VERSION 5.7 ;
BUSBITCHARS "[]" ;
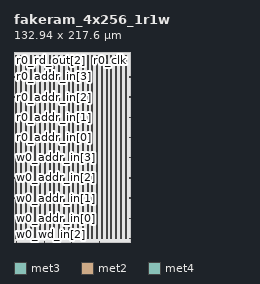
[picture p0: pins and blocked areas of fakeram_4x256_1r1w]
MACRO fakeram_4x256_1r1w
  FOREIGN fakeram_4x256_1r1w 0 0 ;
  SYMMETRY X Y R90 ;
  SIZE 132.940 BY 217.600 ;
  CLASS BLOCK ;
  PIN w0_wd_in[0]
    DIRECTION INPUT ;
    USE SIGNAL ;
    SHAPE ABUTMENT ;
    PORT
      LAYER met3 ;
      RECT 0.000 3.930 0.900 4.230 ;
    END
  END w0_wd_in[0]
  PIN w0_wd_in[1]
    DIRECTION INPUT ;
    USE SIGNAL ;
    SHAPE ABUTMENT ;
    PORT
      LAYER met3 ;
      RECT 132.040 3.930 132.940 4.230 ;
    END
  END w0_wd_in[1]
  PIN w0_wd_in[2]
    DIRECTION INPUT ;
    USE SIGNAL ;
    SHAPE ABUTMENT ;
    PORT
      LAYER met2 ;
      RECT 2.690 0.000 2.830 0.420 ;
    END
  END w0_wd_in[2]
  PIN w0_wd_in[3]
    DIRECTION INPUT ;
    USE SIGNAL ;
    SHAPE ABUTMENT ;
    PORT
      LAYER met2 ;
      RECT 34.430 0.000 34.570 0.420 ;
    END
  END w0_wd_in[3]
  PIN r0_rd_out[0]
    DIRECTION OUTPUT ;
    USE SIGNAL ;
    SHAPE ABUTMENT ;
    PORT
      LAYER met2 ;
      RECT 66.170 0.000 66.310 0.420 ;
    END
  END r0_rd_out[0]
  PIN r0_rd_out[1]
    DIRECTION OUTPUT ;
    USE SIGNAL ;
    SHAPE ABUTMENT ;
    PORT
      LAYER met2 ;
      RECT 97.910 0.000 98.050 0.420 ;
    END
  END r0_rd_out[1]
  PIN r0_rd_out[2]
    DIRECTION OUTPUT ;
    USE SIGNAL ;
    SHAPE ABUTMENT ;
    PORT
      LAYER met2 ;
      RECT 2.690 217.180 2.830 217.600 ;
    END
  END r0_rd_out[2]
  PIN r0_rd_out[3]
    DIRECTION OUTPUT ;
    USE SIGNAL ;
    SHAPE ABUTMENT ;
    PORT
      LAYER met2 ;
      RECT 20.630 217.180 20.770 217.600 ;
    END
  END r0_rd_out[3]
  PIN w0_addr_in[0]
    DIRECTION INPUT ;
    USE SIGNAL ;
    SHAPE ABUTMENT ;
    PORT
      LAYER met3 ;
      RECT 0.000 27.050 0.900 27.350 ;
    END
  END w0_addr_in[0]
  PIN w0_addr_in[1]
    DIRECTION INPUT ;
    USE SIGNAL ;
    SHAPE ABUTMENT ;
    PORT
      LAYER met3 ;
      RECT 0.000 50.170 0.900 50.470 ;
    END
  END w0_addr_in[1]
  PIN w0_addr_in[2]
    DIRECTION INPUT ;
    USE SIGNAL ;
    SHAPE ABUTMENT ;
    PORT
      LAYER met3 ;
      RECT 0.000 73.290 0.900 73.590 ;
    END
  END w0_addr_in[2]
  PIN w0_addr_in[3]
    DIRECTION INPUT ;
    USE SIGNAL ;
    SHAPE ABUTMENT ;
    PORT
      LAYER met3 ;
      RECT 0.000 96.410 0.900 96.710 ;
    END
  END w0_addr_in[3]
  PIN w0_addr_in[4]
    DIRECTION INPUT ;
    USE SIGNAL ;
    SHAPE ABUTMENT ;
    PORT
      LAYER met3 ;
      RECT 132.040 27.050 132.940 27.350 ;
    END
  END w0_addr_in[4]
  PIN w0_addr_in[5]
    DIRECTION INPUT ;
    USE SIGNAL ;
    SHAPE ABUTMENT ;
    PORT
      LAYER met3 ;
      RECT 132.040 50.170 132.940 50.470 ;
    END
  END w0_addr_in[5]
  PIN w0_addr_in[6]
    DIRECTION INPUT ;
    USE SIGNAL ;
    SHAPE ABUTMENT ;
    PORT
      LAYER met3 ;
      RECT 132.040 73.290 132.940 73.590 ;
    END
  END w0_addr_in[6]
  PIN w0_addr_in[7]
    DIRECTION INPUT ;
    USE SIGNAL ;
    SHAPE ABUTMENT ;
    PORT
      LAYER met3 ;
      RECT 132.040 96.410 132.940 96.710 ;
    END
  END w0_addr_in[7]
  PIN r0_addr_in[0]
    DIRECTION INPUT ;
    USE SIGNAL ;
    SHAPE ABUTMENT ;
    PORT
      LAYER met3 ;
      RECT 0.000 119.530 0.900 119.830 ;
    END
  END r0_addr_in[0]
  PIN r0_addr_in[1]
    DIRECTION INPUT ;
    USE SIGNAL ;
    SHAPE ABUTMENT ;
    PORT
      LAYER met3 ;
      RECT 0.000 142.650 0.900 142.950 ;
    END
  END r0_addr_in[1]
  PIN r0_addr_in[2]
    DIRECTION INPUT ;
    USE SIGNAL ;
    SHAPE ABUTMENT ;
    PORT
      LAYER met3 ;
      RECT 0.000 165.770 0.900 166.070 ;
    END
  END r0_addr_in[2]
  PIN r0_addr_in[3]
    DIRECTION INPUT ;
    USE SIGNAL ;
    SHAPE ABUTMENT ;
    PORT
      LAYER met3 ;
      RECT 0.000 188.890 0.900 189.190 ;
    END
  END r0_addr_in[3]
  PIN r0_addr_in[4]
    DIRECTION INPUT ;
    USE SIGNAL ;
    SHAPE ABUTMENT ;
    PORT
      LAYER met3 ;
      RECT 132.040 119.530 132.940 119.830 ;
    END
  END r0_addr_in[4]
  PIN r0_addr_in[5]
    DIRECTION INPUT ;
    USE SIGNAL ;
    SHAPE ABUTMENT ;
    PORT
      LAYER met3 ;
      RECT 132.040 142.650 132.940 142.950 ;
    END
  END r0_addr_in[5]
  PIN r0_addr_in[6]
    DIRECTION INPUT ;
    USE SIGNAL ;
    SHAPE ABUTMENT ;
    PORT
      LAYER met3 ;
      RECT 132.040 165.770 132.940 166.070 ;
    END
  END r0_addr_in[6]
  PIN r0_addr_in[7]
    DIRECTION INPUT ;
    USE SIGNAL ;
    SHAPE ABUTMENT ;
    PORT
      LAYER met3 ;
      RECT 132.040 188.890 132.940 189.190 ;
    END
  END r0_addr_in[7]
  PIN w0_we_in
    DIRECTION INPUT ;
    USE SIGNAL ;
    SHAPE ABUTMENT ;
    PORT
      LAYER met2 ;
      RECT 38.570 217.180 38.710 217.600 ;
    END
  END w0_we_in
  PIN w0_ce_in
    DIRECTION INPUT ;
    USE SIGNAL ;
    SHAPE ABUTMENT ;
    PORT
      LAYER met2 ;
      RECT 56.510 217.180 56.650 217.600 ;
    END
  END w0_ce_in
  PIN w0_clk
    DIRECTION INPUT ;
    USE SIGNAL ;
    SHAPE ABUTMENT ;
    PORT
      LAYER met2 ;
      RECT 74.450 217.180 74.590 217.600 ;
    END
  END w0_clk
  PIN r0_ce_in
    DIRECTION INPUT ;
    USE SIGNAL ;
    SHAPE ABUTMENT ;
    PORT
      LAYER met2 ;
      RECT 92.390 217.180 92.530 217.600 ;
    END
  END r0_ce_in
  PIN r0_clk
    DIRECTION INPUT ;
    USE SIGNAL ;
    SHAPE ABUTMENT ;
    PORT
      LAYER met2 ;
      RECT 110.330 217.180 110.470 217.600 ;
    END
  END r0_clk
  PIN VSS
    DIRECTION INOUT ;
    USE GROUND ;
    PORT
      LAYER met4 ;
      RECT 2.160 4.080 3.360 213.520 ;
      RECT 13.040 4.080 14.240 213.520 ;
      RECT 23.920 4.080 25.120 213.520 ;
      RECT 34.800 4.080 36.000 213.520 ;
      RECT 45.680 4.080 46.880 213.520 ;
      RECT 56.560 4.080 57.760 213.520 ;
      RECT 67.440 4.080 68.640 213.520 ;
      RECT 78.320 4.080 79.520 213.520 ;
      RECT 89.200 4.080 90.400 213.520 ;
      RECT 100.080 4.080 101.280 213.520 ;
      RECT 110.960 4.080 112.160 213.520 ;
      RECT 121.840 4.080 123.040 213.520 ;
    END
  END VSS
  PIN VDD
    DIRECTION INOUT ;
    USE POWER ;
    PORT
      LAYER met4 ;
      RECT 7.600 4.080 8.800 213.520 ;
      RECT 18.480 4.080 19.680 213.520 ;
      RECT 29.360 4.080 30.560 213.520 ;
      RECT 40.240 4.080 41.440 213.520 ;
      RECT 51.120 4.080 52.320 213.520 ;
      RECT 62.000 4.080 63.200 213.520 ;
      RECT 72.880 4.080 74.080 213.520 ;
      RECT 83.760 4.080 84.960 213.520 ;
      RECT 94.640 4.080 95.840 213.520 ;
      RECT 105.520 4.080 106.720 213.520 ;
      RECT 116.400 4.080 117.600 213.520 ;
      RECT 127.280 4.080 128.480 213.520 ;
    END
  END VDD
  OBS
    LAYER met1 ;
    RECT 0 0 132.940 217.600 ;
    LAYER met2 ;
    RECT 0 0 132.940 217.600 ;
    LAYER met3 ;
    RECT 0 0 132.940 217.600 ;
    LAYER met4 ;
    RECT 0 0 132.940 217.600 ;
  END
END fakeram_4x256_1r1w

END LIBRARY
